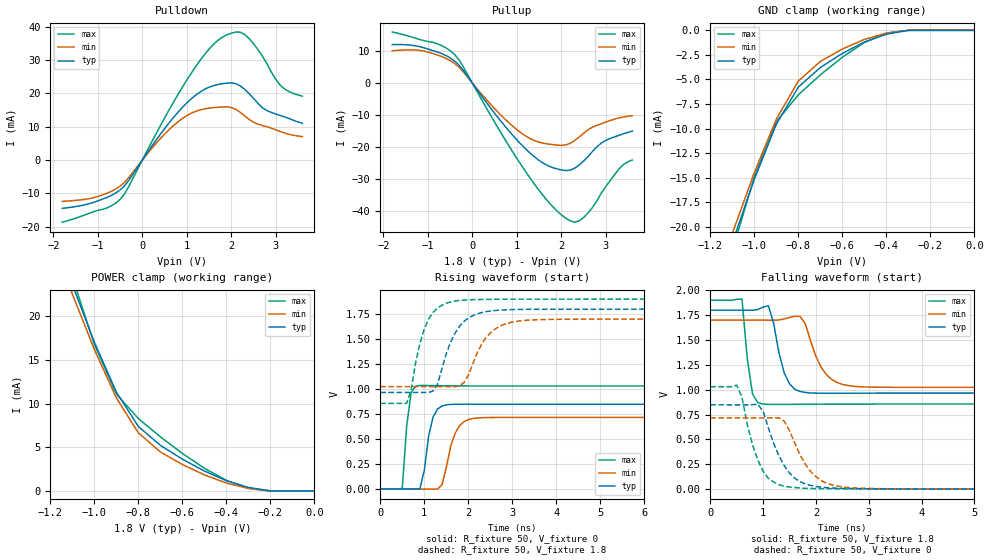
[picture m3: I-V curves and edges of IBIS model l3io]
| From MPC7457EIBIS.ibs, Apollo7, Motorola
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| *   l3io Model   *
[Model]   l3io
Model_type   I/O
Polarity   Non-Inverting
Vinl = 0.63V
Vinh = 1.17V
Vmeas = 0.9V
Cref = 0
Rref = 50
Vref = 0.9V
|   typ   min   max
C_comp   4.937050e-12   3.967321e-12   5.095416e-12
|   typ   min   max
[Voltage range]   1.8V   1.7V   1.9V
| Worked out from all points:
|   slope of the pulldown table from 0 to 0.27 V, typ, clamps not added: 51.5 ohm
|   slope of the pullup table from 0 to 0.27 V, typ, clamps not added: 52 ohm
|   GND clamp passes 1 mA (typ) near -0.48 V on its own axis
|   POWER clamp passes 1 mA (typ) near -0.38 V on its own axis
|   falling waveform, R_fixture 50, V_fixture 1.8: 20-80 % time 221ps typ, 332ps min, 133ps max; typ from 1.8 V to 0.966 V
|   rising waveform, R_fixture 50, V_fixture 0: 20-80 % time 187ps typ, 262ps min, 126ps max; typ from 0 V to 0.848 V
|   falling waveform, R_fixture 50, V_fixture 0: 20-80 % time 427ps typ, 454ps min, 340ps max; typ from 0.848 V to 0 V
|   rising waveform, R_fixture 50, V_fixture 1.8: 20-80 % time 457ps typ, 491ps min, 361ps max; typ from 0.966 V to 1.8 V
[Pulldown]
|   Voltage   I(typ)   I(min)   I(max)
-1.8V     -14.49mA   -12.38mA   -18.64mA
-1.1V     -12.7mA    -11.3mA    -15.51mA
-500mV    -8.983mA   -7.838mA   -11.82mA
-300mV    -6.007mA   -5.154mA   -7.812mA
400mV     7.634mA    6.337mA    10.14mA
900mV     15.76mA    12.46mA    21.82mA
1.5V      21.85mA    15.57mA    33.28mA
1.9V      23.07mA    15.96mA    37.56mA
2.3V      21.24mA    13.28mA    37.68mA
2.7V      15.72mA    10.36mA    31.22mA
3.1V      13.39mA    8.573mA    22.49mA
3.6V      10.99mA    7.026mA    19.17mA
[GND_clamp]
-1.8V     -73.47mA   -70.39mA   -83.19mA
-1.1V     -21.62mA   -20.69mA   -22.45mA
-1V       -15.16mA   -14.48mA   -14.92mA
-900mV    -9.56mA    -9.047mA   -9.303mA
-800mV    -5.776mA   -5.169mA   -6.561mA
-700mV    -3.785mA   -3.168mA   -4.537mA
-600mV    -2.349mA   -1.904mA   -2.734mA
-500mV    -1.19mA    -926.9uA   -1.236mA
-400mV    -393uA     -289.3uA   -277uA
-300mV    0A         0A         0A
0V        0A         0A         0A
[Pullup]
-1.8V     11.99mA    10.08mA    15.89mA
-1.1V     11.04mA    10mA       13.26mA
-700mV    9.251mA    8.317mA    11.73mA
-400mV    6.893mA    6.122mA    8.933mA
500mV     -9.412mA   -7.966mA   -12.17mA
1.1V      -19.17mA   -15.57mA   -25.59mA
1.7V      -25.79mA   -19.01mA   -36.91mA
2.2V      -27.2mA    -18.8mA    -42.98mA
2.5V      -24.39mA   -15.71mA   -41.99mA
2.9V      -18.74mA   -12.71mA   -34.36mA
3.3V      -16.31mA   -10.89mA   -26.78mA
3.6V      -15mA      -10.19mA   -24.02mA
[POWER_clamp]
-1.8V     77.02mA    74.04mA    86.2mA
-1.1V     23.63mA    22.56mA    24.5mA
-1V       17.05mA    16.22mA    16.8mA
-900mV    11.33mA    10.67mA    11.1mA
-800mV    7.384mA    6.654mA    8.295mA
-700mV    5.228mA    4.47mA     6.201mA
-600mV    3.639mA    3.025mA    4.296mA
-500mV    2.282mA    1.842mA    2.601mA
-400mV    1.172mA    904.8uA    1.21mA
-300mV    403.2uA    290.6uA    304uA
-200mV    0A         0A         0A
0V        0A         0A         0A
|   typ   min   max
[Ramp]
dV/dt_r   0.50876/1.75699e-10   0.42973/2.48823e-10   0.61838/9.79055e-11
dV/dt_f   0.50024/2.14736e-10   0.40552/3.28013e-10   0.62600/1.12576e-10
[Falling Waveform]
R_fixture = 50
V_fixture = 1.8
V_fixture_min = 1.7
V_fixture_max = 1.9
| time   V(typ)   V(min)   V(max)
0s        1.8V       1.7V       1.9V
600ps     1.8V       1.7V       1.912V
800ps     1.799V     1.7V       958mV
1ns       1.831V     1.7V       855.8mV
1.1ns     1.845V     1.699V     852.9mV
1.5ns     1.06V      1.727V     853mV
1.9ns     967.5mV    1.489V     854.4mV
2.3ns     964.6mV    1.103V     855.3mV
2.9ns     965.5mV    1.028V     856mV
19.7ns    966.2mV    1.024V     856.6mV
[Rising Waveform]
R_fixture = 50
V_fixture = 0
V_fixture_min = 0
V_fixture_max = 0
| time   V(typ)   V(min)   V(max)
0s        237.9uV    257.1uV    180.9uV
500ps     648.3uV    502.1uV    8.389mV
600ps     677uV      576.8uV    631.8mV
700ps     624.6uV    605uV      964.7mV
900ps     2.291mV    618.5uV    1.036V
1.2ns     721.5mV    -917.6uV   1.035V
1.5ns     842.4mV    215.8mV    1.033V
1.8ns     848.6mV    634.5mV    1.032V
2.2ns     848.6mV    711.1mV    1.031V
19.7ns    848.2mV    716.5mV    1.031V
[Falling Waveform]
R_fixture = 50
V_fixture = 0
V_fixture_min = 0
V_fixture_max = 0
| time   V(typ)   V(min)   V(max)
0s        848.2mV    716.5mV    1.031V
500ps     847.9mV    716.5mV    1.046V
600ps     847.9mV    716.4mV    926.5mV
900ps     853.1mV    716.1mV    294.4mV
1.1ns     616.4mV    716.6mV    109.2mV
1.3ns     334.7mV    717.9mV    45.03mV
1.5ns     161.9mV    589.3mV    21.62mV
2ns       27.2mV     126mV      6.073mV
2.7ns     5.899mV    13.71mV    2.848mV
19.7ns    250.4uV    276.3uV    184.1uV
[Rising Waveform]
R_fixture = 50
V_fixture = 1.8
V_fixture_min = 1.7
V_fixture_max = 1.9
| time   V(typ)   V(min)   V(max)
0s        966.2mV    1.024V     856.6mV
600ps     966.4mV    1.024V     857.4mV
700ps     966.4mV    1.024V     988.6mV
900ps     966.2mV    1.024V     1.455V
1.2ns     980.6mV    1.024V     1.767V
1.7ns     1.56V      1.023V     1.881V
1.9ns     1.676V     1.064V     1.889V
2.5ns     1.78V      1.561V     1.897V
3.3ns     1.797V     1.687V     1.899V
19.7ns    1.8V       1.7V       1.9V
